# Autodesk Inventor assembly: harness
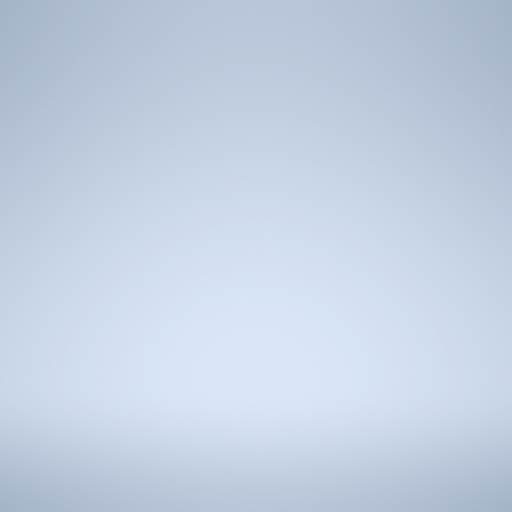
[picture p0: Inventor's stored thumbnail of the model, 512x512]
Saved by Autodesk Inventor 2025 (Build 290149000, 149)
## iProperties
Part Number: harness
Document SubType Name: Assembly
Created: 2002-07
HarnessSettings: <HarnessSettings><Defaults><Segments><Diameter value="0.200 in" fromwires="True"/><Offset value="0.100 in"/><ColorStyle value="Blue"/><BendRadius value="19" fro
Control State: 0
Master: False
Checked Out: False
Shininess: 64.0
Length Units: 11272
Angle Units: 11279
Time Units: 11290
Mass Units: 11286
Length Display Precision: 3
Angle Display Precision: 2
Compacted: True
Density: 0.0
Volumn: 0.0
Area: 0.0
PropertySet Name: Model Information
HarnessSettings: <HarnessSettings><Defaults><Segments><Diameter value="0.200 in" fromwires="True"/><Offset value="0.100 in"/><ColorStyle value="Modrá – nástěnná malba – lesklá"/
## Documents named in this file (1)
- C:\Users\enu\Desktop\CSYTP1\harness.iam
